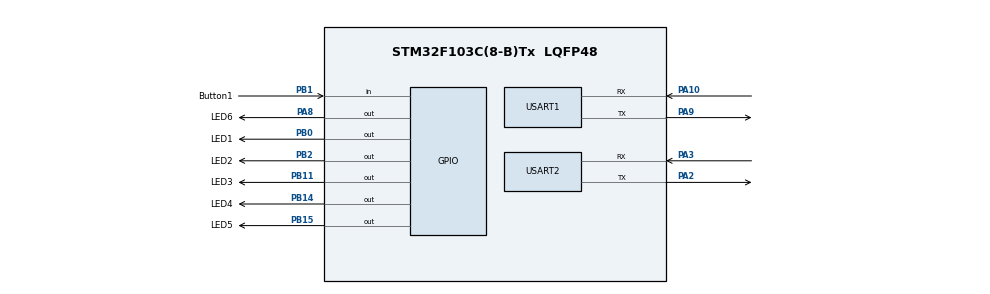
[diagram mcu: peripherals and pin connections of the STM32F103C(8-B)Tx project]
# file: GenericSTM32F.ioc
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Mcu.Family=STM32F1
Mcu.Name=STM32F103C(8-B)Tx
Mcu.Package=LQFP48
NVIC.PriorityGroup=NVIC_PRIORITYGROUP_4
NVIC.USART1_IRQn=true\:0\:0\:false\:false\:true\:true\:true
PA10.Mode=Asynchronous
PA10.Signal=USART1_RX
PA13.Mode=Serial_Wire
PA13.Signal=SYS_JTMS-SWDIO
PA14.Mode=Serial_Wire
PA14.Signal=SYS_JTCK-SWCLK
PA2.Mode=Asynchronous
PA2.Signal=USART2_TX
PA3.Mode=Asynchronous
PA3.Signal=USART2_RX
PA8.GPIO_Label=LED6
PA8.Signal=GPIO_Output
PA9.Mode=Asynchronous
PA9.Signal=USART1_TX
PB0.GPIO_Label=LED1
PB0.Signal=GPIO_Output
PB1.GPIO_Label=Button1
PB1.GPIO_PuPd=GPIO_PULLUP
PB1.Signal=GPIO_Input
PB11.GPIO_Label=LED3
PB11.Signal=GPIO_Output
PB14.GPIO_Label=LED4
PB14.Signal=GPIO_Output
PB15.GPIO_Label=LED5
PB15.Signal=GPIO_Output
PB2.GPIO_Label=LED2
PB2.Signal=GPIO_Output
PD0-OSC_IN.Mode=HSE-External-Oscillator
PD0-OSC_IN.Signal=RCC_OSC_IN
PD1-OSC_OUT.Mode=HSE-External-Oscillator
PD1-OSC_OUT.Signal=RCC_OSC_OUT
ProjectManager.HeapSize=0x200
ProjectManager.StackSize=0x400
ProjectManager.TargetToolchain=STM32CubeIDE
RCC.AHBFreq_Value=72000000
RCC.APB1CLKDivider=RCC_HCLK_DIV2
RCC.APB1Freq_Value=36000000
RCC.APB1TimFreq_Value=72000000
RCC.APB2Freq_Value=72000000
RCC.APB2TimFreq_Value=72000000
RCC.HCLKFreq_Value=72000000
RCC.HSEDivPLL=RCC_HSE_PREDIV_DIV2
RCC.HSE_VALUE=16000000
RCC.PLLMUL=RCC_PLL_MUL9
RCC.PLLSourceVirtual=RCC_PLLSOURCE_HSE
RCC.SYSCLKFreq_VALUE=72000000
RCC.SYSCLKSource=RCC_SYSCLKSOURCE_PLLCLK
RCC.USBFreq_Value=72000000
USART1.VirtualMode=VM_ASYNC
USART2.VirtualMode=VM_ASYNC
board=STM32CubeMX_configuration

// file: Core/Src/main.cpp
/* USER CODE BEGIN Header */
/**
  ******************************************************************************
  * @file           : main.c
  * @brief          : Main program body
  ******************************************************************************
  * @attention
  *
  * <h2><center>&copy; Copyright (c) 2021 STMicroelectronics.
  * All rights reserved.</center></h2>
  *
  * This software component is licensed by ST under BSD 3-Clause license,
  * the "License"; You may not use this file except in compliance with the
  * License. You may obtain a copy of the License at:
  *                        opensource.org/licenses/BSD-3-Clause
  *
  ******************************************************************************
  * @file    main.cpp
  * @author  Ostap Kostyk
  * @brief   main program body
  *
  ******************************************************************************
  * Copyright (C) 2018  Ostap Kostyk
  * This notice applies to any and all portions of this file
  * that are between comment pairs USER CODE BEGIN and
  * USER CODE END.
  *
  * This program is free software: you can redistribute it and/or modify
  * it under the terms of the GNU General Public License as published by
  * the Free Software Foundation, either version 3 of the License, or
  * (at your option) any later version.
  *
  * This program is distributed in the hope that it will be useful,
  * but WITHOUT ANY WARRANTY; without even the implied warranty of
  * MERCHANTABILITY or FITNESS FOR A PARTICULAR PURPOSE.  See the
  * GNU General Public License for more details.
  *
  * You should have received a copy of the GNU General Public License
  * along with this program.  If not, see <http://www.gnu.org/licenses/>.
  ******************************************************************************
  * Author contact information: Ostap Kostyk, email: ostap.kostyk@gmail.com
  ******************************************************************************
  */
/* USER CODE END Header */
#include "main.h"

/* USER CODE BEGIN Includes */
extern "C" {
#include "My_hal_uart_stm32f1xx.h"
#include <stdio.h>
#include "CircularBuffer.h"
#include "eeprom.h"
}
#include "Timer.h"
#include "LED.h"
#include "Button.h"

using namespace mTimer;
/* USER CODE END Includes */

UART_HandleTypeDef huart1;
UART_HandleTypeDef huart2;

/* USER CODE BEGIN PV */
// circular buffer structures (not a buffers themselves) for standard input/output
circular_buffer StdInOut_cb_Rx;
circular_buffer StdInOut_cb_Tx;

#ifdef EEPROM_EMULATION_EN
/* EEPROM Emulation */
/* Virtual address defined by the user: 0xFFFF value is prohibited */
EE_Data_t EE_Data;
uint16_t VirtAddVarTab[NB_OF_VAR];
uint16_t EE_Status;
#endif

#ifdef EXAMPLE_TIMER
Timer TestTimer{};
#endif

/*   LEDs   */
/* Here we create LED instances. Port and Pin declarations came from autogenerated by CubeMX code */
LED   LED2{LED2_GPIO_Port, LED2_Pin, LED::eActiveLevel::High};
LED   LED3{LED3_GPIO_Port, LED3_Pin, LED::eActiveLevel::High};
LED   LED4{LED4_GPIO_Port, LED4_Pin, LED::eActiveLevel::Low};
LED   LED5{LED5_GPIO_Port, LED5_Pin, LED::eActiveLevel::Low};
LED   LED6{LED6_GPIO_Port, LED6_Pin, LED::eActiveLevel::Low};

/*   Buttons  */
/* Here we create Buttons instances. Port and Pin declarations came from autogenerated by CubeMX code */
Button Button1{Button1_GPIO_Port, Button1_Pin, Button::ePressedLevel::Low};

/* Below are sizes of In and Out circular buffers for standard input/output */
#define STD_IN_CB_SIZE      200
#define STD_OUT_CB_SIZE     200
/* USER CODE END PV */

void SystemClock_Config(void);
static void MX_GPIO_Init(void);
static void MX_USART1_UART_Init(void);
static void MX_USART2_UART_Init(void);

/* USER CODE BEGIN 0 */
void BlockingFaultHandler(void)
{
   while(1)
   {

   }
}

void HAL_SYSTICK_Callback(void)
{
//Warning: timers handler below is called from interrupt so can influence application significantly if there are many timers created.
//If this is a problem then the handler should be moved outside interrupt (can be called using global variable incremented here). Timers will be less accurate in this case
Timer::Tick();  //  handles all timers created in IRQ.
}

// Hardware-dependent function called from LED class
void LEDWritePin (GPIO_TypeDef* Port, uint16_t Pin, GPIO_PinState PinState)
{
    HAL_GPIO_WritePin(Port, Pin, PinState);
}

// Hardware-dependent function called from Button class
int ButtonReadPin (PORT_DEF Port, PIN_NUM_DEF Pin)
{
    if(HAL_GPIO_ReadPin(Port, Pin) == GPIO_PIN_SET) { return 1; }

    return 0;
}
/* USER CODE END 0 */

int main(void)
{
  /* USER CODE BEGIN 1 */
	  memmgr_init();

	#ifdef EEPROM_EMULATION_EN
	  /* EEPROM EMULATION-RELATED */
	  EE_AddrInit();
	  /* Unlock the Flash Program Erase controller */
	  HAL_FLASH_Unlock();

	  EE_Status = EE_Init();    //  Init EEPROM Emulation

	  /* END OF EEPROM EMULATION-RELATED */
	#endif

  /* USER CODE END 1 */

  /* MCU Configuration--------------------------------------------------------*/

  /* Reset of all peripherals, Initializes the Flash interface and the Systick. */
  HAL_Init();

  /* Configure the system clock */
  SystemClock_Config();

  /* Initialize all configured peripherals */
  MX_GPIO_Init();
  MX_USART1_UART_Init();
  MX_USART2_UART_Init();
  /* USER CODE BEGIN 2 */
  // Configure UART for std in/out
  if(SUCCESS != Init_USART_CB(&stdinout_huart, &StdInOut_cb_Rx, &StdInOut_cb_Tx, STD_IN_CB_SIZE, STD_OUT_CB_SIZE, sizeof(U8)))
  {
      BlockingFaultHandler();
  }
  Start_USART_Rx_IT(&stdinout_huart);

  // stdout test
  printf("Copyright (c) 2021 Ostap Kostyk\r\n");
  debug_print("START\r\n");
  // End of stdout example

#ifdef EXAMPLE_TIMER
  //Timer example
  TestTimer.Set(_1sec_);
  TestTimer.Reset();
#endif

  // LED example
  LED2.Off();   //  keep LED off by default
  LED3.Off();
  LED4.Blink(_100ms_, _900ms_, true);   //  LED blinks permanently with 0.1sec ON time and 0.9sec OFF time, results in 1-second period
  LED5.Blink(_500ms_, _500ms_, false);
  LED6.Off();

#ifdef EEPROM_EMULATION_EN
  EE_Status = EE_InitData();
  if(EE_Status) { debug_print("EE Data Init ERROR:%x\r\n", EE_Status); }
#endif

#ifdef EEPROM_EMULATION_EN
#if 0
  /* Example of EEPROM Emulation usage */
  EE_Status = EE_ReadElem((uint16_t*)&EE_Data.MyNum32, sizeof(EE_Data.MyNum32));
  if(EE_Status) { debug_print("EE Read Num ERROR: %x\r\n", EE_Status); }

  EE_Status = EE_ReadElem((uint16_t*)&EE_Data.MyString, sizeof(EE_Data.MyString));
  if(EE_Status) { debug_print("EE Read Str ERROR: %x\r\n", EE_Status); }
  else          { debug_print("EE String:%s\r\n", EE_Data.MyString); }

  EE_Data.MyNum32++;
  snprintf(EE_Data.MyString, sizeof(EE_Data.MyString)-1, "This is Start#%d", (int)EE_Data.MyNum32);

  EE_Status = EE_WriteElem((uint16_t*)&EE_Data.MyNum32, sizeof(EE_Data.MyNum32));
  if(EE_Status) { debug_print("EE Write ERROR: %x\r\n", EE_Status); }

  EE_Status = EE_WriteElem((uint16_t*)&EE_Data.MyString, sizeof(EE_Data.MyString));
  if(EE_Status) { debug_print("EE WriteStr ERROR: %x\r\n", EE_Status); }
#endif

#if 1
  /* Example 2 of EEPROM Emulation usage */
  /* The LED blinks as many number of times as the button has been pressed previous run-session before power-off */
  EE_Status = EE_ReadElem((uint16_t*)&EE_Data.MyNum16, sizeof(EE_Data.MyNum16));
  if(EE_Status) { LED6.Blink(_100ms_, _100ms_, true); }
  else          { LED6.BlinkNtimes(_200ms_, _800ms_, (unsigned int)EE_Data.MyNum16); }

  EE_Data.MyNum16 = 0;
  EE_WriteElem((uint16_t*)&EE_Data.MyNum16, sizeof(EE_Data.MyNum16));
#endif

#endif  // END OF #ifdef EEPROM_EMULATION_EN
  /* USER CODE END 2 */

  /* Infinite loop */
  while (1)
  {

/* USER CODE BEGIN 3 */
  // While loop must not be empty, otherwise compiler optimize it and CPU resets right after start

#if 0
  static U32 counter = 0;

  // LED blinking example
  if(counter > 100000)
  {

	HAL_GPIO_WritePin(GPIOB, LED1_Pin, GPIO_PIN_RESET);
  }
  if(counter++ > 800000)
  {
	counter = 0;
	HAL_GPIO_WritePin(GPIOB, LED1_Pin, GPIO_PIN_SET);
  }
  // End of LED blinking
#endif

  // Test LED class
  LED::Ctrl();

  // Test Button Class
  Button::Ctrl();

  if(Button1.GetState() == Button::eState::Pressed)
  {
	  LED2.On();
  }
  else
  {
	  LED2.Off();
  }

  if(Button1.PressedEvent())
  {
	  Button1.ClearPressedEvent();
	  //  turn off LED3 while button is pressed, turn it ON when button released for the time button has been pressed (to test button counters)
	  LED3.Off();

#ifdef EEPROM_EMULATION_EN
	  /* Example 2 of EEPROM Emulation usage */
	  /* The LED will blink, how many times the button was pressed in this work session before shutting down */
	  EE_Data.MyNum16++;
	  EE_Status = EE_WriteElem((uint16_t*)&EE_Data.MyNum16, sizeof(EE_Data.MyNum16));
#endif
  }

  if(Button1.ReleasedEvent())
  {
	  // turn LED ON for the time measured above, while button has been pressed
	  LED3.BlinkNtimes(Button1.GetPressedTime(), _100ms_, 1);
	  Button1.ClearReleasedEvent();
  }

#if 0
	  // Reception from stdin example:
	  char mystr[20] = "";

	  /* Attention! Next line blocks execution of main cycle until user enters text line! */
	  fgets(mystr, 19, stdin);

	  if(strstr(mystr, "ok")) { debug_print("Received\r\n"); }
	  // End of Reception from stdin example
#endif
  }
  /* USER CODE END 3 */
}

void SystemClock_Config(void)
{
	  RCC_OscInitTypeDef RCC_OscInitStruct = {0};
	  RCC_ClkInitTypeDef RCC_ClkInitStruct = {0};

	  /** Initializes the RCC Oscillators according to the specified parameters
	  * in the RCC_OscInitTypeDef structure.
	  */
	  RCC_OscInitStruct.OscillatorType = RCC_OSCILLATORTYPE_HSI;
	  RCC_OscInitStruct.HSIState = RCC_HSI_ON;
	  RCC_OscInitStruct.HSICalibrationValue = RCC_HSICALIBRATION_DEFAULT;
	  RCC_OscInitStruct.PLL.PLLState = RCC_PLL_ON;
	  RCC_OscInitStruct.PLL.PLLSource = RCC_PLLSOURCE_HSI_DIV2;
	  RCC_OscInitStruct.PLL.PLLMUL = RCC_PLL_MUL12;
	  if (HAL_RCC_OscConfig(&RCC_OscInitStruct) != HAL_OK)
	  {
	    Error_Handler();
	  }
	  /** Initializes the CPU, AHB and APB buses clocks
	  */
	  RCC_ClkInitStruct.ClockType = RCC_CLOCKTYPE_HCLK|RCC_CLOCKTYPE_SYSCLK
	                              |RCC_CLOCKTYPE_PCLK1|RCC_CLOCKTYPE_PCLK2;
	  RCC_ClkInitStruct.SYSCLKSource = RCC_SYSCLKSOURCE_PLLCLK;
	  RCC_ClkInitStruct.AHBCLKDivider = RCC_SYSCLK_DIV1;
	  RCC_ClkInitStruct.APB1CLKDivider = RCC_HCLK_DIV2;
	  RCC_ClkInitStruct.APB2CLKDivider = RCC_HCLK_DIV1;

	  if (HAL_RCC_ClockConfig(&RCC_ClkInitStruct, FLASH_LATENCY_1) != HAL_OK)
	  {
	    Error_Handler();
	  }
}

static void MX_USART1_UART_Init(void)
{

  huart1.Instance = USART1;
  huart1.Init.BaudRate = 115200;
  huart1.Init.WordLength = UART_WORDLENGTH_8B;
  huart1.Init.StopBits = UART_STOPBITS_1;
  huart1.Init.Parity = UART_PARITY_NONE;
  huart1.Init.Mode = UART_MODE_TX_RX;
  huart1.Init.HwFlowCtl = UART_HWCONTROL_NONE;
  huart1.Init.OverSampling = UART_OVERSAMPLING_16;
  if (HAL_UART_Init(&huart1) != HAL_OK)
  {
    Error_Handler();
  }

}

static void MX_USART2_UART_Init(void)
{

  huart2.Instance = USART2;
  huart2.Init.BaudRate = 115200;
  huart2.Init.WordLength = UART_WORDLENGTH_8B;
  huart2.Init.StopBits = UART_STOPBITS_1;
  huart2.Init.Parity = UART_PARITY_NONE;
  huart2.Init.Mode = UART_MODE_TX_RX;
  huart2.Init.HwFlowCtl = UART_HWCONTROL_NONE;
  huart2.Init.OverSampling = UART_OVERSAMPLING_16;
  if (HAL_UART_Init(&huart2) != HAL_OK)
  {
    Error_Handler();
  }

}

static void MX_GPIO_Init(void)
{
  GPIO_InitTypeDef GPIO_InitStruct = {0};

  /* GPIO Ports Clock Enable */
  __HAL_RCC_GPIOD_CLK_ENABLE();
  __HAL_RCC_GPIOA_CLK_ENABLE();
  __HAL_RCC_GPIOB_CLK_ENABLE();

  /*Configure GPIO pin Output Level */
  HAL_GPIO_WritePin(GPIOB, LED1_Pin|LED2_Pin|LED3_Pin|LED4_Pin
                          |LED5_Pin, GPIO_PIN_RESET);

  /*Configure GPIO pin Output Level */
  HAL_GPIO_WritePin(LED6_GPIO_Port, LED6_Pin, GPIO_PIN_RESET);

  /*Configure GPIO pins : LED1_Pin LED2_Pin LED3_Pin LED4_Pin
                           LED5_Pin */
  GPIO_InitStruct.Pin = LED1_Pin|LED2_Pin|LED3_Pin|LED4_Pin
                          |LED5_Pin;
  GPIO_InitStruct.Mode = GPIO_MODE_OUTPUT_PP;
  GPIO_InitStruct.Pull = GPIO_NOPULL;
  GPIO_InitStruct.Speed = GPIO_SPEED_FREQ_LOW;
  HAL_GPIO_Init(GPIOB, &GPIO_InitStruct);

  /*Configure GPIO pin : Button1_Pin */
  GPIO_InitStruct.Pin = Button1_Pin;
  GPIO_InitStruct.Mode = GPIO_MODE_INPUT;
  GPIO_InitStruct.Pull = GPIO_PULLUP;
  HAL_GPIO_Init(Button1_GPIO_Port, &GPIO_InitStruct);

  /*Configure GPIO pin : LED6_Pin */
  GPIO_InitStruct.Pin = LED6_Pin;
  GPIO_InitStruct.Mode = GPIO_MODE_OUTPUT_PP;
  GPIO_InitStruct.Pull = GPIO_NOPULL;
  GPIO_InitStruct.Speed = GPIO_SPEED_FREQ_LOW;
  HAL_GPIO_Init(LED6_GPIO_Port, &GPIO_InitStruct);

}

void Error_Handler(void)
{
  __disable_irq();
  while (1)
  {
  }
}

/************************ (C) COPYRIGHT STMicroelectronics *****END OF FILE****/
